VERSION 5.7 ;
  NOWIREEXTENSIONATPIN ON ;
  DIVIDERCHAR "/" ;
  BUSBITCHARS "[]" ;
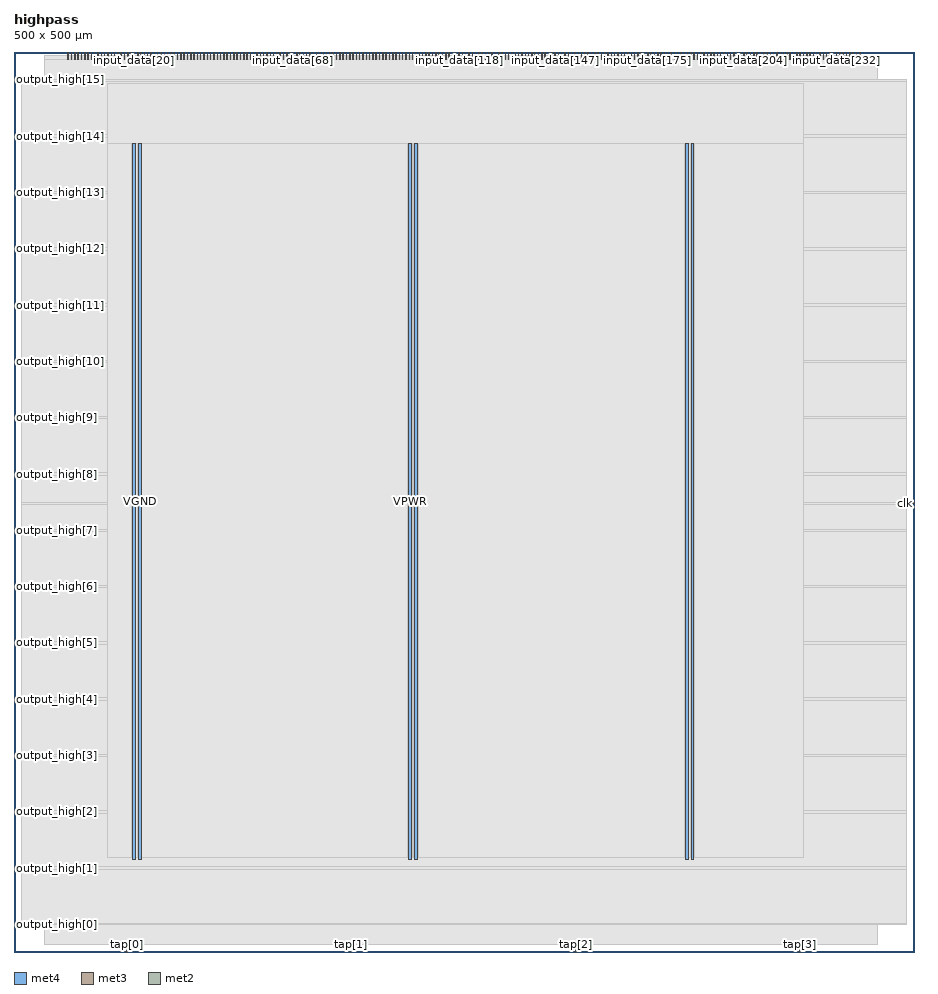
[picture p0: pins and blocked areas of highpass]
MACRO highpass
  CLASS BLOCK ;
  FOREIGN highpass ;
  ORIGIN 0.000 0.000 ;
  SIZE 500.000 BY 500.000 ;
  PIN VGND
    DIRECTION INOUT ;
    USE GROUND ;
    PORT
      LAYER met4 ;
        RECT 68.960 51.440 70.560 449.040 ;
    END
    PORT
      LAYER met4 ;
        RECT 222.560 51.440 224.160 449.040 ;
    END
    PORT
      LAYER met4 ;
        RECT 376.160 51.440 377.760 449.040 ;
    END
  END VGND
  PIN VPWR
    DIRECTION INOUT ;
    USE POWER ;
    PORT
      LAYER met4 ;
        RECT 65.660 51.440 67.260 449.040 ;
    END
    PORT
      LAYER met4 ;
        RECT 219.260 51.440 220.860 449.040 ;
    END
    PORT
      LAYER met4 ;
        RECT 372.860 51.440 374.460 449.040 ;
    END
  END VPWR
  PIN clk
    DIRECTION INPUT ;
    USE SIGNAL ;
    ANTENNAGATEAREA 0.852000 ;
    ANTENNADIFFAREA 0.434700 ;
    PORT
      LAYER met3 ;
        RECT 496.000 248.920 500.000 249.520 ;
    END
  END clk
  PIN input_data[0]
    DIRECTION INPUT ;
    USE SIGNAL ;
    ANTENNAGATEAREA 0.213000 ;
    ANTENNADIFFAREA 0.434700 ;
    PORT
      LAYER met2 ;
        RECT 29.990 496.000 30.270 500.000 ;
    END
  END input_data[0]
  PIN input_data[100]
    DIRECTION INPUT ;
    USE SIGNAL ;
    ANTENNAGATEAREA 0.213000 ;
    ANTENNADIFFAREA 0.434700 ;
    PORT
      LAYER met2 ;
        RECT 213.990 496.000 214.270 500.000 ;
    END
  END input_data[100]
  PIN input_data[101]
    DIRECTION INPUT ;
    USE SIGNAL ;
    ANTENNAGATEAREA 0.196500 ;
    ANTENNADIFFAREA 0.434700 ;
    PORT
      LAYER met2 ;
        RECT 215.830 496.000 216.110 500.000 ;
    END
  END input_data[101]
  PIN input_data[102]
    DIRECTION INPUT ;
    USE SIGNAL ;
    ANTENNAGATEAREA 0.196500 ;
    ANTENNADIFFAREA 0.434700 ;
    PORT
      LAYER met2 ;
        RECT 217.670 496.000 217.950 500.000 ;
    END
  END input_data[102]
  PIN input_data[103]
    DIRECTION INPUT ;
    USE SIGNAL ;
    ANTENNAGATEAREA 0.196500 ;
    ANTENNADIFFAREA 0.434700 ;
    PORT
      LAYER met2 ;
        RECT 219.510 496.000 219.790 500.000 ;
    END
  END input_data[103]
  PIN input_data[104]
    DIRECTION INPUT ;
    USE SIGNAL ;
    ANTENNAGATEAREA 0.196500 ;
    ANTENNADIFFAREA 0.434700 ;
    PORT
      LAYER met2 ;
        RECT 221.350 496.000 221.630 500.000 ;
    END
  END input_data[104]
  PIN input_data[105]
    DIRECTION INPUT ;
    USE SIGNAL ;
    ANTENNAGATEAREA 0.196500 ;
    ANTENNADIFFAREA 0.434700 ;
    PORT
      LAYER met2 ;
        RECT 223.190 496.000 223.470 500.000 ;
    END
  END input_data[105]
  PIN input_data[106]
    DIRECTION INPUT ;
    USE SIGNAL ;
    ANTENNAGATEAREA 0.196500 ;
    ANTENNADIFFAREA 0.434700 ;
    PORT
      LAYER met2 ;
        RECT 225.030 496.000 225.310 500.000 ;
    END
  END input_data[106]
  PIN input_data[107]
    DIRECTION INPUT ;
    USE SIGNAL ;
    ANTENNAGATEAREA 0.196500 ;
    ANTENNADIFFAREA 0.434700 ;
    PORT
      LAYER met2 ;
        RECT 226.870 496.000 227.150 500.000 ;
    END
  END input_data[107]
  PIN input_data[108]
    DIRECTION INPUT ;
    USE SIGNAL ;
    ANTENNAGATEAREA 0.159000 ;
    ANTENNADIFFAREA 0.434700 ;
    PORT
      LAYER met2 ;
        RECT 228.710 496.000 228.990 500.000 ;
    END
  END input_data[108]
  PIN input_data[109]
    DIRECTION INPUT ;
    USE SIGNAL ;
    ANTENNAGATEAREA 0.196500 ;
    ANTENNADIFFAREA 0.434700 ;
    PORT
      LAYER met2 ;
        RECT 230.550 496.000 230.830 500.000 ;
    END
  END input_data[109]
  PIN input_data[10]
    DIRECTION INPUT ;
    USE SIGNAL ;
    ANTENNAGATEAREA 0.247500 ;
    ANTENNADIFFAREA 0.434700 ;
    PORT
      LAYER met2 ;
        RECT 48.390 496.000 48.670 500.000 ;
    END
  END input_data[10]
  PIN input_data[110]
    DIRECTION INPUT ;
    USE SIGNAL ;
    ANTENNAGATEAREA 0.196500 ;
    ANTENNADIFFAREA 0.434700 ;
    PORT
      LAYER met2 ;
        RECT 232.390 496.000 232.670 500.000 ;
    END
  END input_data[110]
  PIN input_data[111]
    DIRECTION INPUT ;
    USE SIGNAL ;
    ANTENNAGATEAREA 0.196500 ;
    ANTENNADIFFAREA 0.434700 ;
    PORT
      LAYER met2 ;
        RECT 234.230 496.000 234.510 500.000 ;
    END
  END input_data[111]
  PIN input_data[112]
    DIRECTION INPUT ;
    USE SIGNAL ;
    ANTENNAGATEAREA 0.213000 ;
    ANTENNADIFFAREA 0.434700 ;
    PORT
      LAYER met2 ;
        RECT 236.070 496.000 236.350 500.000 ;
    END
  END input_data[112]
  PIN input_data[113]
    DIRECTION INPUT ;
    USE SIGNAL ;
    ANTENNAGATEAREA 0.196500 ;
    ANTENNADIFFAREA 0.434700 ;
    PORT
      LAYER met2 ;
        RECT 237.910 496.000 238.190 500.000 ;
    END
  END input_data[113]
  PIN input_data[114]
    DIRECTION INPUT ;
    USE SIGNAL ;
    ANTENNAGATEAREA 0.213000 ;
    ANTENNADIFFAREA 0.434700 ;
    PORT
      LAYER met2 ;
        RECT 239.750 496.000 240.030 500.000 ;
    END
  END input_data[114]
  PIN input_data[115]
    DIRECTION INPUT ;
    USE SIGNAL ;
    ANTENNAGATEAREA 0.213000 ;
    ANTENNADIFFAREA 0.434700 ;
    PORT
      LAYER met2 ;
        RECT 241.590 496.000 241.870 500.000 ;
    END
  END input_data[115]
  PIN input_data[116]
    DIRECTION INPUT ;
    USE SIGNAL ;
    ANTENNAGATEAREA 0.196500 ;
    ANTENNADIFFAREA 0.434700 ;
    PORT
      LAYER met2 ;
        RECT 243.430 496.000 243.710 500.000 ;
    END
  END input_data[116]
  PIN input_data[117]
    DIRECTION INPUT ;
    USE SIGNAL ;
    ANTENNAGATEAREA 0.196500 ;
    ANTENNADIFFAREA 0.434700 ;
    PORT
      LAYER met2 ;
        RECT 245.270 496.000 245.550 500.000 ;
    END
  END input_data[117]
  PIN input_data[118]
    DIRECTION INPUT ;
    USE SIGNAL ;
    ANTENNAGATEAREA 0.196500 ;
    ANTENNADIFFAREA 0.434700 ;
    PORT
      LAYER met2 ;
        RECT 247.110 496.000 247.390 500.000 ;
    END
  END input_data[118]
  PIN input_data[119]
    DIRECTION INPUT ;
    USE SIGNAL ;
    ANTENNAGATEAREA 0.196500 ;
    ANTENNADIFFAREA 0.434700 ;
    PORT
      LAYER met2 ;
        RECT 248.950 496.000 249.230 500.000 ;
    END
  END input_data[119]
  PIN input_data[11]
    DIRECTION INPUT ;
    USE SIGNAL ;
    ANTENNAGATEAREA 0.213000 ;
    ANTENNADIFFAREA 0.434700 ;
    PORT
      LAYER met2 ;
        RECT 50.230 496.000 50.510 500.000 ;
    END
  END input_data[11]
  PIN input_data[120]
    DIRECTION INPUT ;
    USE SIGNAL ;
    ANTENNAGATEAREA 0.196500 ;
    ANTENNADIFFAREA 0.434700 ;
    PORT
      LAYER met2 ;
        RECT 250.790 496.000 251.070 500.000 ;
    END
  END input_data[120]
  PIN input_data[121]
    DIRECTION INPUT ;
    USE SIGNAL ;
    ANTENNAGATEAREA 0.196500 ;
    ANTENNADIFFAREA 0.434700 ;
    PORT
      LAYER met2 ;
        RECT 252.630 496.000 252.910 500.000 ;
    END
  END input_data[121]
  PIN input_data[122]
    DIRECTION INPUT ;
    USE SIGNAL ;
    ANTENNAGATEAREA 0.159000 ;
    ANTENNADIFFAREA 0.434700 ;
    PORT
      LAYER met2 ;
        RECT 254.470 496.000 254.750 500.000 ;
    END
  END input_data[122]
  PIN input_data[123]
    DIRECTION INPUT ;
    USE SIGNAL ;
    ANTENNAGATEAREA 0.159000 ;
    ANTENNADIFFAREA 0.434700 ;
    PORT
      LAYER met2 ;
        RECT 256.310 496.000 256.590 500.000 ;
    END
  END input_data[123]
  PIN input_data[124]
    DIRECTION INPUT ;
    USE SIGNAL ;
    ANTENNAGATEAREA 0.213000 ;
    ANTENNADIFFAREA 0.434700 ;
    PORT
      LAYER met2 ;
        RECT 258.150 496.000 258.430 500.000 ;
    END
  END input_data[124]
  PIN input_data[125]
    DIRECTION INPUT ;
    USE SIGNAL ;
    ANTENNAGATEAREA 0.196500 ;
    ANTENNADIFFAREA 0.434700 ;
    PORT
      LAYER met2 ;
        RECT 259.990 496.000 260.270 500.000 ;
    END
  END input_data[125]
  PIN input_data[126]
    DIRECTION INPUT ;
    USE SIGNAL ;
    ANTENNAGATEAREA 0.196500 ;
    ANTENNADIFFAREA 0.434700 ;
    PORT
      LAYER met2 ;
        RECT 261.830 496.000 262.110 500.000 ;
    END
  END input_data[126]
  PIN input_data[127]
    DIRECTION INPUT ;
    USE SIGNAL ;
    PORT
      LAYER met2 ;
        RECT 263.670 496.000 263.950 500.000 ;
    END
  END input_data[127]
  PIN input_data[128]
    DIRECTION INPUT ;
    USE SIGNAL ;
    ANTENNAGATEAREA 0.196500 ;
    ANTENNADIFFAREA 0.434700 ;
    PORT
      LAYER met2 ;
        RECT 265.510 496.000 265.790 500.000 ;
    END
  END input_data[128]
  PIN input_data[129]
    DIRECTION INPUT ;
    USE SIGNAL ;
    ANTENNAGATEAREA 0.213000 ;
    ANTENNADIFFAREA 0.434700 ;
    PORT
      LAYER met2 ;
        RECT 267.350 496.000 267.630 500.000 ;
    END
  END input_data[129]
  PIN input_data[12]
    DIRECTION INPUT ;
    USE SIGNAL ;
    ANTENNAGATEAREA 0.495000 ;
    ANTENNADIFFAREA 0.434700 ;
    PORT
      LAYER met2 ;
        RECT 52.070 496.000 52.350 500.000 ;
    END
  END input_data[12]
  PIN input_data[130]
    DIRECTION INPUT ;
    USE SIGNAL ;
    ANTENNAGATEAREA 0.213000 ;
    ANTENNADIFFAREA 0.434700 ;
    PORT
      LAYER met2 ;
        RECT 269.190 496.000 269.470 500.000 ;
    END
  END input_data[130]
  PIN input_data[131]
    DIRECTION INPUT ;
    USE SIGNAL ;
    ANTENNAGATEAREA 0.213000 ;
    ANTENNADIFFAREA 0.434700 ;
    PORT
      LAYER met2 ;
        RECT 271.030 496.000 271.310 500.000 ;
    END
  END input_data[131]
  PIN input_data[132]
    DIRECTION INPUT ;
    USE SIGNAL ;
    ANTENNAGATEAREA 0.213000 ;
    ANTENNADIFFAREA 0.434700 ;
    PORT
      LAYER met2 ;
        RECT 272.870 496.000 273.150 500.000 ;
    END
  END input_data[132]
  PIN input_data[133]
    DIRECTION INPUT ;
    USE SIGNAL ;
    ANTENNAGATEAREA 0.247500 ;
    ANTENNADIFFAREA 0.434700 ;
    PORT
      LAYER met2 ;
        RECT 274.710 496.000 274.990 500.000 ;
    END
  END input_data[133]
  PIN input_data[134]
    DIRECTION INPUT ;
    USE SIGNAL ;
    ANTENNAGATEAREA 0.213000 ;
    ANTENNADIFFAREA 0.434700 ;
    PORT
      LAYER met2 ;
        RECT 276.550 496.000 276.830 500.000 ;
    END
  END input_data[134]
  PIN input_data[135]
    DIRECTION INPUT ;
    USE SIGNAL ;
    ANTENNAGATEAREA 0.213000 ;
    ANTENNADIFFAREA 0.434700 ;
    PORT
      LAYER met2 ;
        RECT 278.390 496.000 278.670 500.000 ;
    END
  END input_data[135]
  PIN input_data[136]
    DIRECTION INPUT ;
    USE SIGNAL ;
    ANTENNAGATEAREA 0.495000 ;
    ANTENNADIFFAREA 0.434700 ;
    PORT
      LAYER met2 ;
        RECT 280.230 496.000 280.510 500.000 ;
    END
  END input_data[136]
  PIN input_data[137]
    DIRECTION INPUT ;
    USE SIGNAL ;
    ANTENNAGATEAREA 0.247500 ;
    ANTENNADIFFAREA 0.434700 ;
    PORT
      LAYER met2 ;
        RECT 282.070 496.000 282.350 500.000 ;
    END
  END input_data[137]
  PIN input_data[138]
    DIRECTION INPUT ;
    USE SIGNAL ;
    ANTENNAGATEAREA 0.159000 ;
    ANTENNADIFFAREA 0.434700 ;
    PORT
      LAYER met2 ;
        RECT 283.910 496.000 284.190 500.000 ;
    END
  END input_data[138]
  PIN input_data[139]
    DIRECTION INPUT ;
    USE SIGNAL ;
    ANTENNAGATEAREA 0.247500 ;
    ANTENNADIFFAREA 0.434700 ;
    PORT
      LAYER met2 ;
        RECT 285.750 496.000 286.030 500.000 ;
    END
  END input_data[139]
  PIN input_data[13]
    DIRECTION INPUT ;
    USE SIGNAL ;
    ANTENNAGATEAREA 0.426000 ;
    ANTENNADIFFAREA 0.434700 ;
    PORT
      LAYER met2 ;
        RECT 53.910 496.000 54.190 500.000 ;
    END
  END input_data[13]
  PIN input_data[140]
    DIRECTION INPUT ;
    USE SIGNAL ;
    ANTENNAGATEAREA 0.247500 ;
    ANTENNADIFFAREA 0.434700 ;
    PORT
      LAYER met2 ;
        RECT 287.590 496.000 287.870 500.000 ;
    END
  END input_data[140]
  PIN input_data[141]
    DIRECTION INPUT ;
    USE SIGNAL ;
    ANTENNAGATEAREA 0.213000 ;
    ANTENNADIFFAREA 0.434700 ;
    PORT
      LAYER met2 ;
        RECT 289.430 496.000 289.710 500.000 ;
    END
  END input_data[141]
  PIN input_data[142]
    DIRECTION INPUT ;
    USE SIGNAL ;
    ANTENNAGATEAREA 0.196500 ;
    ANTENNADIFFAREA 0.434700 ;
    PORT
      LAYER met2 ;
        RECT 291.270 496.000 291.550 500.000 ;
    END
  END input_data[142]
  PIN input_data[143]
    DIRECTION INPUT ;
    USE SIGNAL ;
    ANTENNAGATEAREA 0.196500 ;
    ANTENNADIFFAREA 0.434700 ;
    PORT
      LAYER met2 ;
        RECT 293.110 496.000 293.390 500.000 ;
    END
  END input_data[143]
  PIN input_data[144]
    DIRECTION INPUT ;
    USE SIGNAL ;
    ANTENNAGATEAREA 0.196500 ;
    ANTENNADIFFAREA 0.434700 ;
    PORT
      LAYER met2 ;
        RECT 294.950 496.000 295.230 500.000 ;
    END
  END input_data[144]
  PIN input_data[145]
    DIRECTION INPUT ;
    USE SIGNAL ;
    ANTENNAGATEAREA 0.126000 ;
    ANTENNADIFFAREA 0.434700 ;
    PORT
      LAYER met2 ;
        RECT 296.790 496.000 297.070 500.000 ;
    END
  END input_data[145]
  PIN input_data[146]
    DIRECTION INPUT ;
    USE SIGNAL ;
    ANTENNAGATEAREA 0.126000 ;
    ANTENNADIFFAREA 0.434700 ;
    PORT
      LAYER met2 ;
        RECT 298.630 496.000 298.910 500.000 ;
    END
  END input_data[146]
  PIN input_data[147]
    DIRECTION INPUT ;
    USE SIGNAL ;
    ANTENNAGATEAREA 0.159000 ;
    ANTENNADIFFAREA 0.434700 ;
    PORT
      LAYER met2 ;
        RECT 300.470 496.000 300.750 500.000 ;
    END
  END input_data[147]
  PIN input_data[148]
    DIRECTION INPUT ;
    USE SIGNAL ;
    ANTENNAGATEAREA 0.213000 ;
    ANTENNADIFFAREA 0.434700 ;
    PORT
      LAYER met2 ;
        RECT 302.310 496.000 302.590 500.000 ;
    END
  END input_data[148]
  PIN input_data[149]
    DIRECTION INPUT ;
    USE SIGNAL ;
    ANTENNAGATEAREA 0.213000 ;
    ANTENNADIFFAREA 0.434700 ;
    PORT
      LAYER met2 ;
        RECT 304.150 496.000 304.430 500.000 ;
    END
  END input_data[149]
  PIN input_data[14]
    DIRECTION INPUT ;
    USE SIGNAL ;
    ANTENNAGATEAREA 0.159000 ;
    ANTENNADIFFAREA 0.434700 ;
    PORT
      LAYER met2 ;
        RECT 55.750 496.000 56.030 500.000 ;
    END
  END input_data[14]
  PIN input_data[150]
    DIRECTION INPUT ;
    USE SIGNAL ;
    ANTENNAGATEAREA 0.213000 ;
    ANTENNADIFFAREA 0.434700 ;
    PORT
      LAYER met2 ;
        RECT 305.990 496.000 306.270 500.000 ;
    END
  END input_data[150]
  PIN input_data[151]
    DIRECTION INPUT ;
    USE SIGNAL ;
    ANTENNAGATEAREA 0.159000 ;
    ANTENNADIFFAREA 0.434700 ;
    PORT
      LAYER met2 ;
        RECT 307.830 496.000 308.110 500.000 ;
    END
  END input_data[151]
  PIN input_data[152]
    DIRECTION INPUT ;
    USE SIGNAL ;
    ANTENNAGATEAREA 0.213000 ;
    ANTENNADIFFAREA 0.434700 ;
    PORT
      LAYER met2 ;
        RECT 309.670 496.000 309.950 500.000 ;
    END
  END input_data[152]
  PIN input_data[153]
    DIRECTION INPUT ;
    USE SIGNAL ;
    ANTENNAGATEAREA 0.213000 ;
    ANTENNADIFFAREA 0.434700 ;
    PORT
      LAYER met2 ;
        RECT 311.510 496.000 311.790 500.000 ;
    END
  END input_data[153]
  PIN input_data[154]
    DIRECTION INPUT ;
    USE SIGNAL ;
    ANTENNAGATEAREA 0.213000 ;
    ANTENNADIFFAREA 0.434700 ;
    PORT
      LAYER met2 ;
        RECT 313.350 496.000 313.630 500.000 ;
    END
  END input_data[154]
  PIN input_data[155]
    DIRECTION INPUT ;
    USE SIGNAL ;
    ANTENNAGATEAREA 0.196500 ;
    ANTENNADIFFAREA 0.434700 ;
    PORT
      LAYER met2 ;
        RECT 315.190 496.000 315.470 500.000 ;
    END
  END input_data[155]
  PIN input_data[156]
    DIRECTION INPUT ;
    USE SIGNAL ;
    ANTENNAGATEAREA 0.159000 ;
    ANTENNADIFFAREA 0.434700 ;
    PORT
      LAYER met2 ;
        RECT 317.030 496.000 317.310 500.000 ;
    END
  END input_data[156]
  PIN input_data[157]
    DIRECTION INPUT ;
    USE SIGNAL ;
    ANTENNAGATEAREA 0.213000 ;
    ANTENNADIFFAREA 0.434700 ;
    PORT
      LAYER met2 ;
        RECT 318.870 496.000 319.150 500.000 ;
    END
  END input_data[157]
  PIN input_data[158]
    DIRECTION INPUT ;
    USE SIGNAL ;
    ANTENNAGATEAREA 0.196500 ;
    ANTENNADIFFAREA 0.434700 ;
    PORT
      LAYER met2 ;
        RECT 320.710 496.000 320.990 500.000 ;
    END
  END input_data[158]
  PIN input_data[159]
    DIRECTION INPUT ;
    USE SIGNAL ;
    ANTENNAGATEAREA 0.196500 ;
    ANTENNADIFFAREA 0.434700 ;
    PORT
      LAYER met2 ;
        RECT 322.550 496.000 322.830 500.000 ;
    END
  END input_data[159]
  PIN input_data[15]
    DIRECTION INPUT ;
    USE SIGNAL ;
    ANTENNAGATEAREA 0.213000 ;
    ANTENNADIFFAREA 0.434700 ;
    PORT
      LAYER met2 ;
        RECT 57.590 496.000 57.870 500.000 ;
    END
  END input_data[15]
  PIN input_data[160]
    DIRECTION INPUT ;
    USE SIGNAL ;
    ANTENNAGATEAREA 0.247500 ;
    ANTENNADIFFAREA 0.434700 ;
    PORT
      LAYER met2 ;
        RECT 324.390 496.000 324.670 500.000 ;
    END
  END input_data[160]
  PIN input_data[161]
    DIRECTION INPUT ;
    USE SIGNAL ;
    ANTENNAGATEAREA 0.247500 ;
    ANTENNADIFFAREA 0.434700 ;
    PORT
      LAYER met2 ;
        RECT 326.230 496.000 326.510 500.000 ;
    END
  END input_data[161]
  PIN input_data[162]
    DIRECTION INPUT ;
    USE SIGNAL ;
    ANTENNAGATEAREA 0.247500 ;
    ANTENNADIFFAREA 0.434700 ;
    PORT
      LAYER met2 ;
        RECT 328.070 496.000 328.350 500.000 ;
    END
  END input_data[162]
  PIN input_data[163]
    DIRECTION INPUT ;
    USE SIGNAL ;
    ANTENNAGATEAREA 0.213000 ;
    ANTENNADIFFAREA 0.434700 ;
    PORT
      LAYER met2 ;
        RECT 329.910 496.000 330.190 500.000 ;
    END
  END input_data[163]
  PIN input_data[164]
    DIRECTION INPUT ;
    USE SIGNAL ;
    ANTENNAGATEAREA 0.126000 ;
    ANTENNADIFFAREA 0.434700 ;
    PORT
      LAYER met2 ;
        RECT 331.750 496.000 332.030 500.000 ;
    END
  END input_data[164]
  PIN input_data[165]
    DIRECTION INPUT ;
    USE SIGNAL ;
    ANTENNAGATEAREA 0.196500 ;
    ANTENNADIFFAREA 0.434700 ;
    PORT
      LAYER met2 ;
        RECT 333.590 496.000 333.870 500.000 ;
    END
  END input_data[165]
  PIN input_data[166]
    DIRECTION INPUT ;
    USE SIGNAL ;
    ANTENNAGATEAREA 0.126000 ;
    ANTENNADIFFAREA 0.434700 ;
    PORT
      LAYER met2 ;
        RECT 335.430 496.000 335.710 500.000 ;
    END
  END input_data[166]
  PIN input_data[167]
    DIRECTION INPUT ;
    USE SIGNAL ;
    ANTENNAGATEAREA 0.213000 ;
    ANTENNADIFFAREA 0.434700 ;
    PORT
      LAYER met2 ;
        RECT 337.270 496.000 337.550 500.000 ;
    END
  END input_data[167]
  PIN input_data[168]
    DIRECTION INPUT ;
    USE SIGNAL ;
    ANTENNAGATEAREA 0.196500 ;
    ANTENNADIFFAREA 0.434700 ;
    PORT
      LAYER met2 ;
        RECT 339.110 496.000 339.390 500.000 ;
    END
  END input_data[168]
  PIN input_data[169]
    DIRECTION INPUT ;
    USE SIGNAL ;
    ANTENNAGATEAREA 0.196500 ;
    ANTENNADIFFAREA 0.434700 ;
    PORT
      LAYER met2 ;
        RECT 340.950 496.000 341.230 500.000 ;
    END
  END input_data[169]
  PIN input_data[16]
    DIRECTION INPUT ;
    USE SIGNAL ;
    ANTENNAGATEAREA 0.247500 ;
    ANTENNADIFFAREA 0.434700 ;
    PORT
      LAYER met2 ;
        RECT 59.430 496.000 59.710 500.000 ;
    END
  END input_data[16]
  PIN input_data[170]
    DIRECTION INPUT ;
    USE SIGNAL ;
    ANTENNAGATEAREA 0.196500 ;
    ANTENNADIFFAREA 0.434700 ;
    PORT
      LAYER met2 ;
        RECT 342.790 496.000 343.070 500.000 ;
    END
  END input_data[170]
  PIN input_data[171]
    DIRECTION INPUT ;
    USE SIGNAL ;
    ANTENNAGATEAREA 0.213000 ;
    ANTENNADIFFAREA 0.434700 ;
    PORT
      LAYER met2 ;
        RECT 344.630 496.000 344.910 500.000 ;
    END
  END input_data[171]
  PIN input_data[172]
    DIRECTION INPUT ;
    USE SIGNAL ;
    ANTENNAGATEAREA 0.213000 ;
    ANTENNADIFFAREA 0.434700 ;
    PORT
      LAYER met2 ;
        RECT 346.470 496.000 346.750 500.000 ;
    END
  END input_data[172]
  PIN input_data[173]
    DIRECTION INPUT ;
    USE SIGNAL ;
    ANTENNAGATEAREA 0.213000 ;
    ANTENNADIFFAREA 0.434700 ;
    PORT
      LAYER met2 ;
        RECT 348.310 496.000 348.590 500.000 ;
    END
  END input_data[173]
  PIN input_data[174]
    DIRECTION INPUT ;
    USE SIGNAL ;
    ANTENNAGATEAREA 0.196500 ;
    ANTENNADIFFAREA 0.434700 ;
    PORT
      LAYER met2 ;
        RECT 350.150 496.000 350.430 500.000 ;
    END
  END input_data[174]
  PIN input_data[175]
    DIRECTION INPUT ;
    USE SIGNAL ;
    ANTENNAGATEAREA 0.196500 ;
    ANTENNADIFFAREA 0.434700 ;
    PORT
      LAYER met2 ;
        RECT 351.990 496.000 352.270 500.000 ;
    END
  END input_data[175]
  PIN input_data[176]
    DIRECTION INPUT ;
    USE SIGNAL ;
    ANTENNAGATEAREA 0.126000 ;
    ANTENNADIFFAREA 0.434700 ;
    PORT
      LAYER met2 ;
        RECT 353.830 496.000 354.110 500.000 ;
    END
  END input_data[176]
  PIN input_data[177]
    DIRECTION INPUT ;
    USE SIGNAL ;
    ANTENNAGATEAREA 0.213000 ;
    ANTENNADIFFAREA 0.434700 ;
    PORT
      LAYER met2 ;
        RECT 355.670 496.000 355.950 500.000 ;
    END
  END input_data[177]
  PIN input_data[178]
    DIRECTION INPUT ;
    USE SIGNAL ;
    ANTENNAGATEAREA 0.213000 ;
    ANTENNADIFFAREA 0.434700 ;
    PORT
      LAYER met2 ;
        RECT 357.510 496.000 357.790 500.000 ;
    END
  END input_data[178]
  PIN input_data[179]
    DIRECTION INPUT ;
    USE SIGNAL ;
    ANTENNAGATEAREA 0.213000 ;
    ANTENNADIFFAREA 0.434700 ;
    PORT
      LAYER met2 ;
        RECT 359.350 496.000 359.630 500.000 ;
    END
  END input_data[179]
  PIN input_data[17]
    DIRECTION INPUT ;
    USE SIGNAL ;
    ANTENNAGATEAREA 0.247500 ;
    ANTENNADIFFAREA 0.434700 ;
    PORT
      LAYER met2 ;
        RECT 61.270 496.000 61.550 500.000 ;
    END
  END input_data[17]
  PIN input_data[180]
    DIRECTION INPUT ;
    USE SIGNAL ;
    ANTENNAGATEAREA 0.213000 ;
    ANTENNADIFFAREA 0.434700 ;
    PORT
      LAYER met2 ;
        RECT 361.190 496.000 361.470 500.000 ;
    END
  END input_data[180]
  PIN input_data[181]
    DIRECTION INPUT ;
    USE SIGNAL ;
    ANTENNAGATEAREA 0.159000 ;
    ANTENNADIFFAREA 0.434700 ;
    PORT
      LAYER met2 ;
        RECT 363.030 496.000 363.310 500.000 ;
    END
  END input_data[181]
  PIN input_data[182]
    DIRECTION INPUT ;
    USE SIGNAL ;
    ANTENNAGATEAREA 0.159000 ;
    ANTENNADIFFAREA 0.434700 ;
    PORT
      LAYER met2 ;
        RECT 364.870 496.000 365.150 500.000 ;
    END
  END input_data[182]
  PIN input_data[183]
    DIRECTION INPUT ;
    USE SIGNAL ;
    ANTENNAGATEAREA 0.159000 ;
    ANTENNADIFFAREA 0.434700 ;
    PORT
      LAYER met2 ;
        RECT 366.710 496.000 366.990 500.000 ;
    END
  END input_data[183]
  PIN input_data[184]
    DIRECTION INPUT ;
    USE SIGNAL ;
    ANTENNAGATEAREA 0.159000 ;
    ANTENNADIFFAREA 0.434700 ;
    PORT
      LAYER met2 ;
        RECT 368.550 496.000 368.830 500.000 ;
    END
  END input_data[184]
  PIN input_data[185]
    DIRECTION INPUT ;
    USE SIGNAL ;
    ANTENNAGATEAREA 0.213000 ;
    ANTENNADIFFAREA 0.434700 ;
    PORT
      LAYER met2 ;
        RECT 370.390 496.000 370.670 500.000 ;
    END
  END input_data[185]
  PIN input_data[186]
    DIRECTION INPUT ;
    USE SIGNAL ;
    ANTENNAGATEAREA 0.213000 ;
    ANTENNADIFFAREA 0.434700 ;
    PORT
      LAYER met2 ;
        RECT 372.230 496.000 372.510 500.000 ;
    END
  END input_data[186]
  PIN input_data[187]
    DIRECTION INPUT ;
    USE SIGNAL ;
    ANTENNAGATEAREA 0.213000 ;
    ANTENNADIFFAREA 0.434700 ;
    PORT
      LAYER met2 ;
        RECT 374.070 496.000 374.350 500.000 ;
    END
  END input_data[187]
  PIN input_data[188]
    DIRECTION INPUT ;
    USE SIGNAL ;
    ANTENNAGATEAREA 0.159000 ;
    ANTENNADIFFAREA 0.434700 ;
    PORT
      LAYER met2 ;
        RECT 375.910 496.000 376.190 500.000 ;
    END
  END input_data[188]
  PIN input_data[189]
    DIRECTION INPUT ;
    USE SIGNAL ;
    ANTENNAGATEAREA 0.196500 ;
    ANTENNADIFFAREA 0.434700 ;
    PORT
      LAYER met2 ;
        RECT 377.750 496.000 378.030 500.000 ;
    END
  END input_data[189]
  PIN input_data[18]
    DIRECTION INPUT ;
    USE SIGNAL ;
    ANTENNAGATEAREA 0.213000 ;
    ANTENNADIFFAREA 0.434700 ;
    PORT
      LAYER met2 ;
        RECT 63.110 496.000 63.390 500.000 ;
    END
  END input_data[18]
  PIN input_data[190]
    DIRECTION INPUT ;
    USE SIGNAL ;
    ANTENNAGATEAREA 0.196500 ;
    ANTENNADIFFAREA 0.434700 ;
    PORT
      LAYER met2 ;
        RECT 379.590 496.000 379.870 500.000 ;
    END
  END input_data[190]
  PIN input_data[191]
    DIRECTION INPUT ;
    USE SIGNAL ;
    PORT
      LAYER met2 ;
        RECT 381.430 496.000 381.710 500.000 ;
    END
  END input_data[191]
  PIN input_data[192]
    DIRECTION INPUT ;
    USE SIGNAL ;
    ANTENNAGATEAREA 0.213000 ;
    ANTENNADIFFAREA 0.434700 ;
    PORT
      LAYER met2 ;
        RECT 383.270 496.000 383.550 500.000 ;
    END
  END input_data[192]
  PIN input_data[193]
    DIRECTION INPUT ;
    USE SIGNAL ;
    ANTENNAGATEAREA 0.126000 ;
    ANTENNADIFFAREA 0.434700 ;
    PORT
      LAYER met2 ;
        RECT 385.110 496.000 385.390 500.000 ;
    END
  END input_data[193]
  PIN input_data[194]
    DIRECTION INPUT ;
    USE SIGNAL ;
    ANTENNAGATEAREA 0.213000 ;
    ANTENNADIFFAREA 0.434700 ;
    PORT
      LAYER met2 ;
        RECT 386.950 496.000 387.230 500.000 ;
    END
  END input_data[194]
  PIN input_data[195]
    DIRECTION INPUT ;
    USE SIGNAL ;
    ANTENNAGATEAREA 0.213000 ;
    ANTENNADIFFAREA 0.434700 ;
    PORT
      LAYER met2 ;
        RECT 388.790 496.000 389.070 500.000 ;
    END
  END input_data[195]
  PIN input_data[196]
    DIRECTION INPUT ;
    USE SIGNAL ;
    ANTENNAGATEAREA 0.213000 ;
    ANTENNADIFFAREA 0.434700 ;
    PORT
      LAYER met2 ;
        RECT 390.630 496.000 390.910 500.000 ;
    END
  END input_data[196]
  PIN input_data[197]
    DIRECTION INPUT ;
    USE SIGNAL ;
    ANTENNAGATEAREA 0.126000 ;
    ANTENNADIFFAREA 0.434700 ;
    PORT
      LAYER met2 ;
        RECT 392.470 496.000 392.750 500.000 ;
    END
  END input_data[197]
  PIN input_data[198]
    DIRECTION INPUT ;
    USE SIGNAL ;
    ANTENNAGATEAREA 0.126000 ;
    ANTENNADIFFAREA 0.434700 ;
    PORT
      LAYER met2 ;
        RECT 394.310 496.000 394.590 500.000 ;
    END
  END input_data[198]
  PIN input_data[199]
    DIRECTION INPUT ;
    USE SIGNAL ;
    ANTENNAGATEAREA 0.126000 ;
    ANTENNADIFFAREA 0.434700 ;
    PORT
      LAYER met2 ;
        RECT 396.150 496.000 396.430 500.000 ;
    END
  END input_data[199]
  PIN input_data[19]
    DIRECTION INPUT ;
    USE SIGNAL ;
    ANTENNAGATEAREA 0.247500 ;
    ANTENNADIFFAREA 0.434700 ;
    PORT
      LAYER met2 ;
        RECT 64.950 496.000 65.230 500.000 ;
    END
  END input_data[19]
  PIN input_data[1]
    DIRECTION INPUT ;
    USE SIGNAL ;
    ANTENNAGATEAREA 0.159000 ;
    ANTENNADIFFAREA 0.434700 ;
    PORT
      LAYER met2 ;
        RECT 31.830 496.000 32.110 500.000 ;
    END
  END input_data[1]
  PIN input_data[200]
    DIRECTION INPUT ;
    USE SIGNAL ;
    ANTENNAGATEAREA 0.126000 ;
    ANTENNADIFFAREA 0.434700 ;
    PORT
      LAYER met2 ;
        RECT 397.990 496.000 398.270 500.000 ;
    END
  END input_data[200]
  PIN input_data[201]
    DIRECTION INPUT ;
    USE SIGNAL ;
    ANTENNAGATEAREA 0.126000 ;
    ANTENNADIFFAREA 0.434700 ;
    PORT
      LAYER met2 ;
        RECT 399.830 496.000 400.110 500.000 ;
    END
  END input_data[201]
  PIN input_data[202]
    DIRECTION INPUT ;
    USE SIGNAL ;
    ANTENNAGATEAREA 0.126000 ;
    ANTENNADIFFAREA 0.434700 ;
    PORT
      LAYER met2 ;
        RECT 401.670 496.000 401.950 500.000 ;
    END
  END input_data[202]
  PIN input_data[203]
    DIRECTION INPUT ;
    USE SIGNAL ;
    ANTENNAGATEAREA 0.126000 ;
    ANTENNADIFFAREA 0.434700 ;
    PORT
      LAYER met2 ;
        RECT 403.510 496.000 403.790 500.000 ;
    END
  END input_data[203]
  PIN input_data[204]
    DIRECTION INPUT ;
    USE SIGNAL ;
    ANTENNAGATEAREA 0.196500 ;
    ANTENNADIFFAREA 0.434700 ;
    PORT
      LAYER met2 ;
        RECT 405.350 496.000 405.630 500.000 ;
    END
  END input_data[204]
  PIN input_data[205]
    DIRECTION INPUT ;
    USE SIGNAL ;
    ANTENNAGATEAREA 0.196500 ;
    ANTENNADIFFAREA 0.434700 ;
    PORT
      LAYER met2 ;
        RECT 407.190 496.000 407.470 500.000 ;
    END
  END input_data[205]
  PIN input_data[206]
    DIRECTION INPUT ;
    USE SIGNAL ;
    ANTENNAGATEAREA 0.196500 ;
    ANTENNADIFFAREA 0.434700 ;
    PORT
      LAYER met2 ;
        RECT 409.030 496.000 409.310 500.000 ;
    END
  END input_data[206]
  PIN input_data[207]
    DIRECTION INPUT ;
    USE SIGNAL ;
    PORT
      LAYER met2 ;
        RECT 410.870 496.000 411.150 500.000 ;
    END
  END input_data[207]
  PIN input_data[208]
    DIRECTION INPUT ;
    USE SIGNAL ;
    PORT
      LAYER met2 ;
        RECT 412.710 496.000 412.990 500.000 ;
    END
  END input_data[208]
  PIN input_data[209]
    DIRECTION INPUT ;
    USE SIGNAL ;
    PORT
      LAYER met2 ;
        RECT 414.550 496.000 414.830 500.000 ;
    END
  END input_data[209]
  PIN input_data[20]
    DIRECTION INPUT ;
    USE SIGNAL ;
    ANTENNAGATEAREA 0.247500 ;
    ANTENNADIFFAREA 0.434700 ;
    PORT
      LAYER met2 ;
        RECT 66.790 496.000 67.070 500.000 ;
    END
  END input_data[20]
  PIN input_data[210]
    DIRECTION INPUT ;
    USE SIGNAL ;
    PORT
      LAYER met2 ;
        RECT 416.390 496.000 416.670 500.000 ;
    END
  END input_data[210]
  PIN input_data[211]
    DIRECTION INPUT ;
    USE SIGNAL ;
    PORT
      LAYER met2 ;
        RECT 418.230 496.000 418.510 500.000 ;
    END
  END input_data[211]
  PIN input_data[212]
    DIRECTION INPUT ;
    USE SIGNAL ;
    PORT
      LAYER met2 ;
        RECT 420.070 496.000 420.350 500.000 ;
    END
  END input_data[212]
  PIN input_data[213]
    DIRECTION INPUT ;
    USE SIGNAL ;
    PORT
      LAYER met2 ;
        RECT 421.910 496.000 422.190 500.000 ;
    END
  END input_data[213]
  PIN input_data[214]
    DIRECTION INPUT ;
    USE SIGNAL ;
    PORT
      LAYER met2 ;
        RECT 423.750 496.000 424.030 500.000 ;
    END
  END input_data[214]
  PIN input_data[215]
    DIRECTION INPUT ;
    USE SIGNAL ;
    PORT
      LAYER met2 ;
        RECT 425.590 496.000 425.870 500.000 ;
    END
  END input_data[215]
  PIN input_data[216]
    DIRECTION INPUT ;
    USE SIGNAL ;
    PORT
      LAYER met2 ;
        RECT 427.430 496.000 427.710 500.000 ;
    END
  END input_data[216]
  PIN input_data[217]
    DIRECTION INPUT ;
    USE SIGNAL ;
    PORT
      LAYER met2 ;
        RECT 429.270 496.000 429.550 500.000 ;
    END
  END input_data[217]
  PIN input_data[218]
    DIRECTION INPUT ;
    USE SIGNAL ;
    PORT
      LAYER met2 ;
        RECT 431.110 496.000 431.390 500.000 ;
    END
  END input_data[218]
  PIN input_data[219]
    DIRECTION INPUT ;
    USE SIGNAL ;
    PORT
      LAYER met2 ;
        RECT 432.950 496.000 433.230 500.000 ;
    END
  END input_data[219]
  PIN input_data[21]
    DIRECTION INPUT ;
    USE SIGNAL ;
    ANTENNAGATEAREA 0.247500 ;
    ANTENNADIFFAREA 0.434700 ;
    PORT
      LAYER met2 ;
        RECT 68.630 496.000 68.910 500.000 ;
    END
  END input_data[21]
  PIN input_data[220]
    DIRECTION INPUT ;
    USE SIGNAL ;
    PORT
      LAYER met2 ;
        RECT 434.790 496.000 435.070 500.000 ;
    END
  END input_data[220]
  PIN input_data[221]
    DIRECTION INPUT ;
    USE SIGNAL ;
    PORT
      LAYER met2 ;
        RECT 436.630 496.000 436.910 500.000 ;
    END
  END input_data[221]
  PIN input_data[222]
    DIRECTION INPUT ;
    USE SIGNAL ;
    PORT
      LAYER met2 ;
        RECT 438.470 496.000 438.750 500.000 ;
    END
  END input_data[222]
  PIN input_data[223]
    DIRECTION INPUT ;
    USE SIGNAL ;
    PORT
      LAYER met2 ;
        RECT 440.310 496.000 440.590 500.000 ;
    END
  END input_data[223]
  PIN input_data[224]
    DIRECTION INPUT ;
    USE SIGNAL ;
    ANTENNAGATEAREA 0.213000 ;
    ANTENNADIFFAREA 0.434700 ;
    PORT
      LAYER met2 ;
        RECT 442.150 496.000 442.430 500.000 ;
    END
  END input_data[224]
  PIN input_data[225]
    DIRECTION INPUT ;
    USE SIGNAL ;
    ANTENNAGATEAREA 0.247500 ;
    ANTENNADIFFAREA 0.434700 ;
    PORT
      LAYER met2 ;
        RECT 443.990 496.000 444.270 500.000 ;
    END
  END input_data[225]
  PIN input_data[226]
    DIRECTION INPUT ;
    USE SIGNAL ;
    ANTENNAGATEAREA 0.213000 ;
    ANTENNADIFFAREA 0.434700 ;
    PORT
      LAYER met2 ;
        RECT 445.830 496.000 446.110 500.000 ;
    END
  END input_data[226]
  PIN input_data[227]
    DIRECTION INPUT ;
    USE SIGNAL ;
    ANTENNAGATEAREA 0.213000 ;
    ANTENNADIFFAREA 0.434700 ;
    PORT
      LAYER met2 ;
        RECT 447.670 496.000 447.950 500.000 ;
    END
  END input_data[227]
  PIN input_data[228]
    DIRECTION INPUT ;
    USE SIGNAL ;
    ANTENNAGATEAREA 0.213000 ;
    ANTENNADIFFAREA 0.434700 ;
    PORT
      LAYER met2 ;
        RECT 449.510 496.000 449.790 500.000 ;
    END
  END input_data[228]
  PIN input_data[229]
    DIRECTION INPUT ;
    USE SIGNAL ;
    ANTENNAGATEAREA 0.213000 ;
    ANTENNADIFFAREA 0.434700 ;
    PORT
      LAYER met2 ;
        RECT 451.350 496.000 451.630 500.000 ;
    END
  END input_data[229]
  PIN input_data[22]
    DIRECTION INPUT ;
    USE SIGNAL ;
    ANTENNAGATEAREA 0.247500 ;
    ANTENNADIFFAREA 0.434700 ;
    PORT
      LAYER met2 ;
        RECT 70.470 496.000 70.750 500.000 ;
    END
  END input_data[22]
  PIN input_data[230]
    DIRECTION INPUT ;
    USE SIGNAL ;
    ANTENNAGATEAREA 0.213000 ;
    ANTENNADIFFAREA 0.434700 ;
    PORT
      LAYER met2 ;
        RECT 453.190 496.000 453.470 500.000 ;
    END
  END input_data[230]
  PIN input_data[231]
    DIRECTION INPUT ;
    USE SIGNAL ;
    ANTENNAGATEAREA 0.213000 ;
    ANTENNADIFFAREA 0.434700 ;
    PORT
      LAYER met2 ;
        RECT 455.030 496.000 455.310 500.000 ;
    END
  END input_data[231]
  PIN input_data[232]
    DIRECTION INPUT ;
    USE SIGNAL ;
    ANTENNAGATEAREA 0.126000 ;
    ANTENNADIFFAREA 0.434700 ;
    PORT
      LAYER met2 ;
        RECT 456.870 496.000 457.150 500.000 ;
    END
  END input_data[232]
  PIN input_data[233]
    DIRECTION INPUT ;
    USE SIGNAL ;
    ANTENNAGATEAREA 0.126000 ;
    ANTENNADIFFAREA 0.434700 ;
    PORT
      LAYER met2 ;
        RECT 458.710 496.000 458.990 500.000 ;
    END
  END input_data[233]
  PIN input_data[234]
    DIRECTION INPUT ;
    USE SIGNAL ;
    ANTENNAGATEAREA 0.126000 ;
    ANTENNADIFFAREA 0.434700 ;
    PORT
      LAYER met2 ;
        RECT 460.550 496.000 460.830 500.000 ;
    END
  END input_data[234]
  PIN input_data[235]
    DIRECTION INPUT ;
    USE SIGNAL ;
    ANTENNAGATEAREA 0.196500 ;
    ANTENNADIFFAREA 0.434700 ;
    PORT
      LAYER met2 ;
        RECT 462.390 496.000 462.670 500.000 ;
    END
  END input_data[235]
  PIN input_data[236]
    DIRECTION INPUT ;
    USE SIGNAL ;
    ANTENNAGATEAREA 0.196500 ;
    ANTENNADIFFAREA 0.434700 ;
    PORT
      LAYER met2 ;
        RECT 464.230 496.000 464.510 500.000 ;
    END
  END input_data[236]
  PIN input_data[237]
    DIRECTION INPUT ;
    USE SIGNAL ;
    ANTENNAGATEAREA 0.196500 ;
    ANTENNADIFFAREA 0.434700 ;
    PORT
      LAYER met2 ;
        RECT 466.070 496.000 466.350 500.000 ;
    END
  END input_data[237]
  PIN input_data[238]
    DIRECTION INPUT ;
    USE SIGNAL ;
    PORT
      LAYER met2 ;
        RECT 467.910 496.000 468.190 500.000 ;
    END
  END input_data[238]
  PIN input_data[239]
    DIRECTION INPUT ;
    USE SIGNAL ;
    PORT
      LAYER met2 ;
        RECT 469.750 496.000 470.030 500.000 ;
    END
  END input_data[239]
  PIN input_data[23]
    DIRECTION INPUT ;
    USE SIGNAL ;
    ANTENNAGATEAREA 0.247500 ;
    ANTENNADIFFAREA 0.434700 ;
    PORT
      LAYER met2 ;
        RECT 72.310 496.000 72.590 500.000 ;
    END
  END input_data[23]
  PIN input_data[24]
    DIRECTION INPUT ;
    USE SIGNAL ;
    ANTENNAGATEAREA 0.247500 ;
    ANTENNADIFFAREA 0.434700 ;
    PORT
      LAYER met2 ;
        RECT 74.150 496.000 74.430 500.000 ;
    END
  END input_data[24]
  PIN input_data[25]
    DIRECTION INPUT ;
    USE SIGNAL ;
    ANTENNAGATEAREA 0.213000 ;
    ANTENNADIFFAREA 0.434700 ;
    PORT
      LAYER met2 ;
        RECT 75.990 496.000 76.270 500.000 ;
    END
  END input_data[25]
  PIN input_data[26]
    DIRECTION INPUT ;
    USE SIGNAL ;
    ANTENNAGATEAREA 0.213000 ;
    ANTENNADIFFAREA 0.434700 ;
    PORT
      LAYER met2 ;
        RECT 77.830 496.000 78.110 500.000 ;
    END
  END input_data[26]
  PIN input_data[27]
    DIRECTION INPUT ;
    USE SIGNAL ;
    ANTENNAGATEAREA 0.247500 ;
    ANTENNADIFFAREA 0.434700 ;
    PORT
      LAYER met2 ;
        RECT 79.670 496.000 79.950 500.000 ;
    END
  END input_data[27]
  PIN input_data[28]
    DIRECTION INPUT ;
    USE SIGNAL ;
    ANTENNAGATEAREA 0.196500 ;
    ANTENNADIFFAREA 0.434700 ;
    PORT
      LAYER met2 ;
        RECT 81.510 496.000 81.790 500.000 ;
    END
  END input_data[28]
  PIN input_data[29]
    DIRECTION INPUT ;
    USE SIGNAL ;
    ANTENNAGATEAREA 0.247500 ;
    ANTENNADIFFAREA 0.434700 ;
    PORT
      LAYER met2 ;
        RECT 83.350 496.000 83.630 500.000 ;
    END
  END input_data[29]
  PIN input_data[2]
    DIRECTION INPUT ;
    USE SIGNAL ;
    ANTENNAGATEAREA 0.159000 ;
    ANTENNADIFFAREA 0.434700 ;
    PORT
      LAYER met2 ;
        RECT 33.670 496.000 33.950 500.000 ;
    END
  END input_data[2]
  PIN input_data[30]
    DIRECTION INPUT ;
    USE SIGNAL ;
    ANTENNAGATEAREA 0.159000 ;
    ANTENNADIFFAREA 0.434700 ;
    PORT
      LAYER met2 ;
        RECT 85.190 496.000 85.470 500.000 ;
    END
  END input_data[30]
  PIN input_data[31]
    DIRECTION INPUT ;
    USE SIGNAL ;
    ANTENNAGATEAREA 0.126000 ;
    ANTENNADIFFAREA 0.434700 ;
    PORT
      LAYER met2 ;
        RECT 87.030 496.000 87.310 500.000 ;
    END
  END input_data[31]
  PIN input_data[32]
    DIRECTION INPUT ;
    USE SIGNAL ;
    ANTENNAGATEAREA 0.213000 ;
    ANTENNADIFFAREA 0.434700 ;
    PORT
      LAYER met2 ;
        RECT 88.870 496.000 89.150 500.000 ;
    END
  END input_data[32]
  PIN input_data[33]
    DIRECTION INPUT ;
    USE SIGNAL ;
    ANTENNAGATEAREA 0.213000 ;
    ANTENNADIFFAREA 0.434700 ;
    PORT
      LAYER met2 ;
        RECT 90.710 496.000 90.990 500.000 ;
    END
  END input_data[33]
  PIN input_data[34]
    DIRECTION INPUT ;
    USE SIGNAL ;
    ANTENNAGATEAREA 0.159000 ;
    ANTENNADIFFAREA 0.434700 ;
    PORT
      LAYER met2 ;
        RECT 92.550 496.000 92.830 500.000 ;
    END
  END input_data[34]
  PIN input_data[35]
    DIRECTION INPUT ;
    USE SIGNAL ;
    ANTENNAGATEAREA 0.213000 ;
    ANTENNADIFFAREA 0.434700 ;
    PORT
      LAYER met2 ;
        RECT 94.390 496.000 94.670 500.000 ;
    END
  END input_data[35]
  PIN input_data[36]
    DIRECTION INPUT ;
    USE SIGNAL ;
    ANTENNAGATEAREA 0.213000 ;
    ANTENNADIFFAREA 0.434700 ;
    PORT
      LAYER met2 ;
        RECT 96.230 496.000 96.510 500.000 ;
    END
  END input_data[36]
  PIN input_data[37]
    DIRECTION INPUT ;
    USE SIGNAL ;
    ANTENNAGATEAREA 0.213000 ;
    ANTENNADIFFAREA 0.434700 ;
    PORT
      LAYER met2 ;
        RECT 98.070 496.000 98.350 500.000 ;
    END
  END input_data[37]
  PIN input_data[38]
    DIRECTION INPUT ;
    USE SIGNAL ;
    ANTENNAGATEAREA 0.213000 ;
    ANTENNADIFFAREA 0.434700 ;
    PORT
      LAYER met2 ;
        RECT 99.910 496.000 100.190 500.000 ;
    END
  END input_data[38]
  PIN input_data[39]
    DIRECTION INPUT ;
    USE SIGNAL ;
    ANTENNAGATEAREA 0.126000 ;
    ANTENNADIFFAREA 0.434700 ;
    PORT
      LAYER met2 ;
        RECT 101.750 496.000 102.030 500.000 ;
    END
  END input_data[39]
  PIN input_data[3]
    DIRECTION INPUT ;
    USE SIGNAL ;
    ANTENNAGATEAREA 0.159000 ;
    ANTENNADIFFAREA 0.434700 ;
    PORT
      LAYER met2 ;
        RECT 35.510 496.000 35.790 500.000 ;
    END
  END input_data[3]
  PIN input_data[40]
    DIRECTION INPUT ;
    USE SIGNAL ;
    ANTENNAGATEAREA 0.196500 ;
    ANTENNADIFFAREA 0.434700 ;
    PORT
      LAYER met2 ;
        RECT 103.590 496.000 103.870 500.000 ;
    END
  END input_data[40]
  PIN input_data[41]
    DIRECTION INPUT ;
    USE SIGNAL ;
    ANTENNAGATEAREA 0.196500 ;
    ANTENNADIFFAREA 0.434700 ;
    PORT
      LAYER met2 ;
        RECT 105.430 496.000 105.710 500.000 ;
    END
  END input_data[41]
  PIN input_data[42]
    DIRECTION INPUT ;
    USE SIGNAL ;
    ANTENNAGATEAREA 0.196500 ;
    ANTENNADIFFAREA 0.434700 ;
    PORT
      LAYER met2 ;
        RECT 107.270 496.000 107.550 500.000 ;
    END
  END input_data[42]
  PIN input_data[43]
    DIRECTION INPUT ;
    USE SIGNAL ;
    ANTENNAGATEAREA 0.126000 ;
    ANTENNADIFFAREA 0.434700 ;
    PORT
      LAYER met2 ;
        RECT 109.110 496.000 109.390 500.000 ;
    END
  END input_data[43]
  PIN input_data[44]
    DIRECTION INPUT ;
    USE SIGNAL ;
    ANTENNAGATEAREA 0.247500 ;
    ANTENNADIFFAREA 0.434700 ;
    PORT
      LAYER met2 ;
        RECT 110.950 496.000 111.230 500.000 ;
    END
  END input_data[44]
  PIN input_data[45]
    DIRECTION INPUT ;
    USE SIGNAL ;
    ANTENNAGATEAREA 0.213000 ;
    ANTENNADIFFAREA 0.434700 ;
    PORT
      LAYER met2 ;
        RECT 112.790 496.000 113.070 500.000 ;
    END
  END input_data[45]
  PIN input_data[46]
    DIRECTION INPUT ;
    USE SIGNAL ;
    ANTENNAGATEAREA 0.196500 ;
    ANTENNADIFFAREA 0.434700 ;
    PORT
      LAYER met2 ;
        RECT 114.630 496.000 114.910 500.000 ;
    END
  END input_data[46]
  PIN input_data[47]
    DIRECTION INPUT ;
    USE SIGNAL ;
    ANTENNAGATEAREA 0.196500 ;
    ANTENNADIFFAREA 0.434700 ;
    PORT
      LAYER met2 ;
        RECT 116.470 496.000 116.750 500.000 ;
    END
  END input_data[47]
  PIN input_data[48]
    DIRECTION INPUT ;
    USE SIGNAL ;
    ANTENNAGATEAREA 0.196500 ;
    ANTENNADIFFAREA 0.434700 ;
    PORT
      LAYER met2 ;
        RECT 118.310 496.000 118.590 500.000 ;
    END
  END input_data[48]
  PIN input_data[49]
    DIRECTION INPUT ;
    USE SIGNAL ;
    ANTENNAGATEAREA 0.126000 ;
    ANTENNADIFFAREA 0.434700 ;
    PORT
      LAYER met2 ;
        RECT 120.150 496.000 120.430 500.000 ;
    END
  END input_data[49]
  PIN input_data[4]
    DIRECTION INPUT ;
    USE SIGNAL ;
    ANTENNAGATEAREA 0.159000 ;
    ANTENNADIFFAREA 0.434700 ;
    PORT
      LAYER met2 ;
        RECT 37.350 496.000 37.630 500.000 ;
    END
  END input_data[4]
  PIN input_data[50]
    DIRECTION INPUT ;
    USE SIGNAL ;
    ANTENNAGATEAREA 0.196500 ;
    ANTENNADIFFAREA 0.434700 ;
    PORT
      LAYER met2 ;
        RECT 121.990 496.000 122.270 500.000 ;
    END
  END input_data[50]
  PIN input_data[51]
    DIRECTION INPUT ;
    USE SIGNAL ;
    ANTENNAGATEAREA 0.196500 ;
    ANTENNADIFFAREA 0.434700 ;
    PORT
      LAYER met2 ;
        RECT 123.830 496.000 124.110 500.000 ;
    END
  END input_data[51]
  PIN input_data[52]
    DIRECTION INPUT ;
    USE SIGNAL ;
    ANTENNAGATEAREA 0.196500 ;
    ANTENNADIFFAREA 0.434700 ;
    PORT
      LAYER met2 ;
        RECT 125.670 496.000 125.950 500.000 ;
    END
  END input_data[52]
  PIN input_data[53]
    DIRECTION INPUT ;
    USE SIGNAL ;
    ANTENNAGATEAREA 0.126000 ;
    ANTENNADIFFAREA 0.434700 ;
    PORT
      LAYER met2 ;
        RECT 127.510 496.000 127.790 500.000 ;
    END
  END input_data[53]
  PIN input_data[54]
    DIRECTION INPUT ;
    USE SIGNAL ;
    ANTENNAGATEAREA 0.213000 ;
    ANTENNADIFFAREA 0.434700 ;
    PORT
      LAYER met2 ;
        RECT 129.350 496.000 129.630 500.000 ;
    END
  END input_data[54]
  PIN input_data[55]
    DIRECTION INPUT ;
    USE SIGNAL ;
    ANTENNAGATEAREA 0.196500 ;
    ANTENNADIFFAREA 0.434700 ;
    PORT
      LAYER met2 ;
        RECT 131.190 496.000 131.470 500.000 ;
    END
  END input_data[55]
  PIN input_data[56]
    DIRECTION INPUT ;
    USE SIGNAL ;
    ANTENNAGATEAREA 0.213000 ;
    ANTENNADIFFAREA 0.434700 ;
    PORT
      LAYER met2 ;
        RECT 133.030 496.000 133.310 500.000 ;
    END
  END input_data[56]
  PIN input_data[57]
    DIRECTION INPUT ;
    USE SIGNAL ;
    ANTENNAGATEAREA 0.126000 ;
    ANTENNADIFFAREA 0.434700 ;
    PORT
      LAYER met2 ;
        RECT 134.870 496.000 135.150 500.000 ;
    END
  END input_data[57]
  PIN input_data[58]
    DIRECTION INPUT ;
    USE SIGNAL ;
    ANTENNAGATEAREA 0.213000 ;
    ANTENNADIFFAREA 0.434700 ;
    PORT
      LAYER met2 ;
        RECT 136.710 496.000 136.990 500.000 ;
    END
  END input_data[58]
  PIN input_data[59]
    DIRECTION INPUT ;
    USE SIGNAL ;
    ANTENNAGATEAREA 0.247500 ;
    ANTENNADIFFAREA 0.434700 ;
    PORT
      LAYER met2 ;
        RECT 138.550 496.000 138.830 500.000 ;
    END
  END input_data[59]
  PIN input_data[5]
    DIRECTION INPUT ;
    USE SIGNAL ;
    ANTENNAGATEAREA 0.159000 ;
    ANTENNADIFFAREA 0.434700 ;
    PORT
      LAYER met2 ;
        RECT 39.190 496.000 39.470 500.000 ;
    END
  END input_data[5]
  PIN input_data[60]
    DIRECTION INPUT ;
    USE SIGNAL ;
    ANTENNAGATEAREA 0.159000 ;
    ANTENNADIFFAREA 0.434700 ;
    PORT
      LAYER met2 ;
        RECT 140.390 496.000 140.670 500.000 ;
    END
  END input_data[60]
  PIN input_data[61]
    DIRECTION INPUT ;
    USE SIGNAL ;
    ANTENNAGATEAREA 0.213000 ;
    ANTENNADIFFAREA 0.434700 ;
    PORT
      LAYER met2 ;
        RECT 142.230 496.000 142.510 500.000 ;
    END
  END input_data[61]
  PIN input_data[62]
    DIRECTION INPUT ;
    USE SIGNAL ;
    ANTENNAGATEAREA 0.213000 ;
    ANTENNADIFFAREA 0.434700 ;
    PORT
      LAYER met2 ;
        RECT 144.070 496.000 144.350 500.000 ;
    END
  END input_data[62]
  PIN input_data[63]
    DIRECTION INPUT ;
    USE SIGNAL ;
    PORT
      LAYER met2 ;
        RECT 145.910 496.000 146.190 500.000 ;
    END
  END input_data[63]
  PIN input_data[64]
    DIRECTION INPUT ;
    USE SIGNAL ;
    ANTENNAGATEAREA 0.213000 ;
    ANTENNADIFFAREA 0.434700 ;
    PORT
      LAYER met2 ;
        RECT 147.750 496.000 148.030 500.000 ;
    END
  END input_data[64]
  PIN input_data[65]
    DIRECTION INPUT ;
    USE SIGNAL ;
    ANTENNAGATEAREA 0.247500 ;
    ANTENNADIFFAREA 0.434700 ;
    PORT
      LAYER met2 ;
        RECT 149.590 496.000 149.870 500.000 ;
    END
  END input_data[65]
  PIN input_data[66]
    DIRECTION INPUT ;
    USE SIGNAL ;
    ANTENNAGATEAREA 0.196500 ;
    ANTENNADIFFAREA 0.434700 ;
    PORT
      LAYER met2 ;
        RECT 151.430 496.000 151.710 500.000 ;
    END
  END input_data[66]
  PIN input_data[67]
    DIRECTION INPUT ;
    USE SIGNAL ;
    ANTENNAGATEAREA 0.196500 ;
    ANTENNADIFFAREA 0.434700 ;
    PORT
      LAYER met2 ;
        RECT 153.270 496.000 153.550 500.000 ;
    END
  END input_data[67]
  PIN input_data[68]
    DIRECTION INPUT ;
    USE SIGNAL ;
    ANTENNAGATEAREA 0.213000 ;
    ANTENNADIFFAREA 0.434700 ;
    PORT
      LAYER met2 ;
        RECT 155.110 496.000 155.390 500.000 ;
    END
  END input_data[68]
  PIN input_data[69]
    DIRECTION INPUT ;
    USE SIGNAL ;
    ANTENNAGATEAREA 0.196500 ;
    ANTENNADIFFAREA 0.434700 ;
    PORT
      LAYER met2 ;
        RECT 156.950 496.000 157.230 500.000 ;
    END
  END input_data[69]
  PIN input_data[6]
    DIRECTION INPUT ;
    USE SIGNAL ;
    ANTENNAGATEAREA 0.159000 ;
    ANTENNADIFFAREA 0.434700 ;
    PORT
      LAYER met2 ;
        RECT 41.030 496.000 41.310 500.000 ;
    END
  END input_data[6]
  PIN input_data[70]
    DIRECTION INPUT ;
    USE SIGNAL ;
    ANTENNAGATEAREA 0.196500 ;
    ANTENNADIFFAREA 0.434700 ;
    PORT
      LAYER met2 ;
        RECT 158.790 496.000 159.070 500.000 ;
    END
  END input_data[70]
  PIN input_data[71]
    DIRECTION INPUT ;
    USE SIGNAL ;
    ANTENNAGATEAREA 0.196500 ;
    ANTENNADIFFAREA 0.434700 ;
    PORT
      LAYER met2 ;
        RECT 160.630 496.000 160.910 500.000 ;
    END
  END input_data[71]
  PIN input_data[72]
    DIRECTION INPUT ;
    USE SIGNAL ;
    ANTENNAGATEAREA 0.196500 ;
    ANTENNADIFFAREA 0.434700 ;
    PORT
      LAYER met2 ;
        RECT 162.470 496.000 162.750 500.000 ;
    END
  END input_data[72]
  PIN input_data[73]
    DIRECTION INPUT ;
    USE SIGNAL ;
    ANTENNAGATEAREA 0.213000 ;
    ANTENNADIFFAREA 0.434700 ;
    PORT
      LAYER met2 ;
        RECT 164.310 496.000 164.590 500.000 ;
    END
  END input_data[73]
  PIN input_data[74]
    DIRECTION INPUT ;
    USE SIGNAL ;
    ANTENNAGATEAREA 0.196500 ;
    ANTENNADIFFAREA 0.434700 ;
    PORT
      LAYER met2 ;
        RECT 166.150 496.000 166.430 500.000 ;
    END
  END input_data[74]
  PIN input_data[75]
    DIRECTION INPUT ;
    USE SIGNAL ;
    ANTENNAGATEAREA 0.196500 ;
    ANTENNADIFFAREA 0.434700 ;
    PORT
      LAYER met2 ;
        RECT 167.990 496.000 168.270 500.000 ;
    END
  END input_data[75]
  PIN input_data[76]
    DIRECTION INPUT ;
    USE SIGNAL ;
    ANTENNAGATEAREA 0.196500 ;
    ANTENNADIFFAREA 0.434700 ;
    PORT
      LAYER met2 ;
        RECT 169.830 496.000 170.110 500.000 ;
    END
  END input_data[76]
  PIN input_data[77]
    DIRECTION INPUT ;
    USE SIGNAL ;
    ANTENNAGATEAREA 0.213000 ;
    ANTENNADIFFAREA 0.434700 ;
    PORT
      LAYER met2 ;
        RECT 171.670 496.000 171.950 500.000 ;
    END
  END input_data[77]
  PIN input_data[78]
    DIRECTION INPUT ;
    USE SIGNAL ;
    ANTENNAGATEAREA 0.196500 ;
    ANTENNADIFFAREA 0.434700 ;
    PORT
      LAYER met2 ;
        RECT 173.510 496.000 173.790 500.000 ;
    END
  END input_data[78]
  PIN input_data[79]
    DIRECTION INPUT ;
    USE SIGNAL ;
    PORT
      LAYER met2 ;
        RECT 175.350 496.000 175.630 500.000 ;
    END
  END input_data[79]
  PIN input_data[7]
    DIRECTION INPUT ;
    USE SIGNAL ;
    ANTENNAGATEAREA 0.213000 ;
    ANTENNADIFFAREA 0.434700 ;
    PORT
      LAYER met2 ;
        RECT 42.870 496.000 43.150 500.000 ;
    END
  END input_data[7]
  PIN input_data[80]
    DIRECTION INPUT ;
    USE SIGNAL ;
    ANTENNAGATEAREA 0.213000 ;
    ANTENNADIFFAREA 0.434700 ;
    PORT
      LAYER met2 ;
        RECT 177.190 496.000 177.470 500.000 ;
    END
  END input_data[80]
  PIN input_data[81]
    DIRECTION INPUT ;
    USE SIGNAL ;
    ANTENNAGATEAREA 0.159000 ;
    ANTENNADIFFAREA 0.434700 ;
    PORT
      LAYER met2 ;
        RECT 179.030 496.000 179.310 500.000 ;
    END
  END input_data[81]
  PIN input_data[82]
    DIRECTION INPUT ;
    USE SIGNAL ;
    ANTENNAGATEAREA 0.159000 ;
    ANTENNADIFFAREA 0.434700 ;
    PORT
      LAYER met2 ;
        RECT 180.870 496.000 181.150 500.000 ;
    END
  END input_data[82]
  PIN input_data[83]
    DIRECTION INPUT ;
    USE SIGNAL ;
    ANTENNAGATEAREA 0.159000 ;
    ANTENNADIFFAREA 0.434700 ;
    PORT
      LAYER met2 ;
        RECT 182.710 496.000 182.990 500.000 ;
    END
  END input_data[83]
  PIN input_data[84]
    DIRECTION INPUT ;
    USE SIGNAL ;
    ANTENNAGATEAREA 0.159000 ;
    ANTENNADIFFAREA 0.434700 ;
    PORT
      LAYER met2 ;
        RECT 184.550 496.000 184.830 500.000 ;
    END
  END input_data[84]
  PIN input_data[85]
    DIRECTION INPUT ;
    USE SIGNAL ;
    ANTENNAGATEAREA 0.213000 ;
    ANTENNADIFFAREA 0.434700 ;
    PORT
      LAYER met2 ;
        RECT 186.390 496.000 186.670 500.000 ;
    END
  END input_data[85]
  PIN input_data[86]
    DIRECTION INPUT ;
    USE SIGNAL ;
    ANTENNAGATEAREA 0.247500 ;
    ANTENNADIFFAREA 0.434700 ;
    PORT
      LAYER met2 ;
        RECT 188.230 496.000 188.510 500.000 ;
    END
  END input_data[86]
  PIN input_data[87]
    DIRECTION INPUT ;
    USE SIGNAL ;
    ANTENNAGATEAREA 0.247500 ;
    ANTENNADIFFAREA 0.434700 ;
    PORT
      LAYER met2 ;
        RECT 190.070 496.000 190.350 500.000 ;
    END
  END input_data[87]
  PIN input_data[88]
    DIRECTION INPUT ;
    USE SIGNAL ;
    ANTENNAGATEAREA 0.247500 ;
    ANTENNADIFFAREA 0.434700 ;
    PORT
      LAYER met2 ;
        RECT 191.910 496.000 192.190 500.000 ;
    END
  END input_data[88]
  PIN input_data[89]
    DIRECTION INPUT ;
    USE SIGNAL ;
    ANTENNAGATEAREA 0.159000 ;
    ANTENNADIFFAREA 0.434700 ;
    PORT
      LAYER met2 ;
        RECT 193.750 496.000 194.030 500.000 ;
    END
  END input_data[89]
  PIN input_data[8]
    DIRECTION INPUT ;
    USE SIGNAL ;
    ANTENNAGATEAREA 0.159000 ;
    ANTENNADIFFAREA 0.434700 ;
    PORT
      LAYER met2 ;
        RECT 44.710 496.000 44.990 500.000 ;
    END
  END input_data[8]
  PIN input_data[90]
    DIRECTION INPUT ;
    USE SIGNAL ;
    ANTENNAGATEAREA 0.159000 ;
    ANTENNADIFFAREA 0.434700 ;
    PORT
      LAYER met2 ;
        RECT 195.590 496.000 195.870 500.000 ;
    END
  END input_data[90]
  PIN input_data[91]
    DIRECTION INPUT ;
    USE SIGNAL ;
    ANTENNAGATEAREA 0.247500 ;
    ANTENNADIFFAREA 0.434700 ;
    PORT
      LAYER met2 ;
        RECT 197.430 496.000 197.710 500.000 ;
    END
  END input_data[91]
  PIN input_data[92]
    DIRECTION INPUT ;
    USE SIGNAL ;
    ANTENNAGATEAREA 0.213000 ;
    ANTENNADIFFAREA 0.434700 ;
    PORT
      LAYER met2 ;
        RECT 199.270 496.000 199.550 500.000 ;
    END
  END input_data[92]
  PIN input_data[93]
    DIRECTION INPUT ;
    USE SIGNAL ;
    ANTENNAGATEAREA 0.247500 ;
    ANTENNADIFFAREA 0.434700 ;
    PORT
      LAYER met2 ;
        RECT 201.110 496.000 201.390 500.000 ;
    END
  END input_data[93]
  PIN input_data[94]
    DIRECTION INPUT ;
    USE SIGNAL ;
    ANTENNAGATEAREA 0.213000 ;
    ANTENNADIFFAREA 0.434700 ;
    PORT
      LAYER met2 ;
        RECT 202.950 496.000 203.230 500.000 ;
    END
  END input_data[94]
  PIN input_data[95]
    DIRECTION INPUT ;
    USE SIGNAL ;
    ANTENNAGATEAREA 0.196500 ;
    ANTENNADIFFAREA 0.434700 ;
    PORT
      LAYER met2 ;
        RECT 204.790 496.000 205.070 500.000 ;
    END
  END input_data[95]
  PIN input_data[96]
    DIRECTION INPUT ;
    USE SIGNAL ;
    ANTENNAGATEAREA 0.196500 ;
    ANTENNADIFFAREA 0.434700 ;
    PORT
      LAYER met2 ;
        RECT 206.630 496.000 206.910 500.000 ;
    END
  END input_data[96]
  PIN input_data[97]
    DIRECTION INPUT ;
    USE SIGNAL ;
    ANTENNAGATEAREA 0.196500 ;
    ANTENNADIFFAREA 0.434700 ;
    PORT
      LAYER met2 ;
        RECT 208.470 496.000 208.750 500.000 ;
    END
  END input_data[97]
  PIN input_data[98]
    DIRECTION INPUT ;
    USE SIGNAL ;
    ANTENNAGATEAREA 0.213000 ;
    ANTENNADIFFAREA 0.434700 ;
    PORT
      LAYER met2 ;
        RECT 210.310 496.000 210.590 500.000 ;
    END
  END input_data[98]
  PIN input_data[99]
    DIRECTION INPUT ;
    USE SIGNAL ;
    ANTENNAGATEAREA 0.196500 ;
    ANTENNADIFFAREA 0.434700 ;
    PORT
      LAYER met2 ;
        RECT 212.150 496.000 212.430 500.000 ;
    END
  END input_data[99]
  PIN input_data[9]
    DIRECTION INPUT ;
    USE SIGNAL ;
    ANTENNAGATEAREA 0.213000 ;
    ANTENNADIFFAREA 0.434700 ;
    PORT
      LAYER met2 ;
        RECT 46.550 496.000 46.830 500.000 ;
    END
  END input_data[9]
  PIN output_high[0]
    DIRECTION OUTPUT ;
    USE SIGNAL ;
    ANTENNADIFFAREA 0.795200 ;
    PORT
      LAYER met3 ;
        RECT 0.000 15.000 4.000 15.600 ;
    END
  END output_high[0]
  PIN output_high[10]
    DIRECTION OUTPUT ;
    USE SIGNAL ;
    ANTENNADIFFAREA 0.795200 ;
    PORT
      LAYER met3 ;
        RECT 0.000 327.800 4.000 328.400 ;
    END
  END output_high[10]
  PIN output_high[11]
    DIRECTION OUTPUT ;
    USE SIGNAL ;
    ANTENNADIFFAREA 0.795200 ;
    PORT
      LAYER met3 ;
        RECT 0.000 359.080 4.000 359.680 ;
    END
  END output_high[11]
  PIN output_high[12]
    DIRECTION OUTPUT ;
    USE SIGNAL ;
    ANTENNADIFFAREA 0.795200 ;
    PORT
      LAYER met3 ;
        RECT 0.000 390.360 4.000 390.960 ;
    END
  END output_high[12]
  PIN output_high[13]
    DIRECTION OUTPUT ;
    USE SIGNAL ;
    ANTENNADIFFAREA 0.795200 ;
    PORT
      LAYER met3 ;
        RECT 0.000 421.640 4.000 422.240 ;
    END
  END output_high[13]
  PIN output_high[14]
    DIRECTION OUTPUT ;
    USE SIGNAL ;
    ANTENNADIFFAREA 0.795200 ;
    PORT
      LAYER met3 ;
        RECT 0.000 452.920 4.000 453.520 ;
    END
  END output_high[14]
  PIN output_high[15]
    DIRECTION OUTPUT ;
    USE SIGNAL ;
    ANTENNADIFFAREA 0.795200 ;
    PORT
      LAYER met3 ;
        RECT 0.000 484.200 4.000 484.800 ;
    END
  END output_high[15]
  PIN output_high[1]
    DIRECTION OUTPUT ;
    USE SIGNAL ;
    ANTENNADIFFAREA 0.795200 ;
    PORT
      LAYER met3 ;
        RECT 0.000 46.280 4.000 46.880 ;
    END
  END output_high[1]
  PIN output_high[2]
    DIRECTION OUTPUT ;
    USE SIGNAL ;
    ANTENNADIFFAREA 0.795200 ;
    PORT
      LAYER met3 ;
        RECT 0.000 77.560 4.000 78.160 ;
    END
  END output_high[2]
  PIN output_high[3]
    DIRECTION OUTPUT ;
    USE SIGNAL ;
    ANTENNADIFFAREA 0.795200 ;
    PORT
      LAYER met3 ;
        RECT 0.000 108.840 4.000 109.440 ;
    END
  END output_high[3]
  PIN output_high[4]
    DIRECTION OUTPUT ;
    USE SIGNAL ;
    ANTENNADIFFAREA 0.795200 ;
    PORT
      LAYER met3 ;
        RECT 0.000 140.120 4.000 140.720 ;
    END
  END output_high[4]
  PIN output_high[5]
    DIRECTION OUTPUT ;
    USE SIGNAL ;
    ANTENNADIFFAREA 0.795200 ;
    PORT
      LAYER met3 ;
        RECT 0.000 171.400 4.000 172.000 ;
    END
  END output_high[5]
  PIN output_high[6]
    DIRECTION OUTPUT ;
    USE SIGNAL ;
    ANTENNADIFFAREA 0.795200 ;
    PORT
      LAYER met3 ;
        RECT 0.000 202.680 4.000 203.280 ;
    END
  END output_high[6]
  PIN output_high[7]
    DIRECTION OUTPUT ;
    USE SIGNAL ;
    ANTENNADIFFAREA 0.795200 ;
    PORT
      LAYER met3 ;
        RECT 0.000 233.960 4.000 234.560 ;
    END
  END output_high[7]
  PIN output_high[8]
    DIRECTION OUTPUT ;
    USE SIGNAL ;
    ANTENNADIFFAREA 0.795200 ;
    PORT
      LAYER met3 ;
        RECT 0.000 265.240 4.000 265.840 ;
    END
  END output_high[8]
  PIN output_high[9]
    DIRECTION OUTPUT ;
    USE SIGNAL ;
    ANTENNADIFFAREA 0.795200 ;
    PORT
      LAYER met3 ;
        RECT 0.000 296.520 4.000 297.120 ;
    END
  END output_high[9]
  PIN tap[0]
    DIRECTION INPUT ;
    USE SIGNAL ;
    ANTENNAGATEAREA 0.213000 ;
    ANTENNADIFFAREA 0.434700 ;
    PORT
      LAYER met2 ;
        RECT 62.650 0.000 62.930 4.000 ;
    END
  END tap[0]
  PIN tap[1]
    DIRECTION INPUT ;
    USE SIGNAL ;
    ANTENNAGATEAREA 0.213000 ;
    ANTENNADIFFAREA 0.434700 ;
    PORT
      LAYER met2 ;
        RECT 187.310 0.000 187.590 4.000 ;
    END
  END tap[1]
  PIN tap[2]
    DIRECTION INPUT ;
    USE SIGNAL ;
    ANTENNAGATEAREA 0.213000 ;
    ANTENNADIFFAREA 0.434700 ;
    PORT
      LAYER met2 ;
        RECT 311.970 0.000 312.250 4.000 ;
    END
  END tap[2]
  PIN tap[3]
    DIRECTION INPUT ;
    USE SIGNAL ;
    ANTENNAGATEAREA 0.247500 ;
    ANTENNADIFFAREA 0.434700 ;
    PORT
      LAYER met2 ;
        RECT 436.630 0.000 436.910 4.000 ;
    END
  END tap[3]
  OBS
      LAYER li1 ;
        RECT 50.140 51.595 449.880 448.885 ;
      LAYER met1 ;
        RECT 17.090 51.440 466.370 497.040 ;
      LAYER met2 ;
        RECT 17.110 495.720 29.710 498.170 ;
        RECT 30.550 495.720 31.550 498.170 ;
        RECT 32.390 495.720 33.390 498.170 ;
        RECT 34.230 495.720 35.230 498.170 ;
        RECT 36.070 495.720 37.070 498.170 ;
        RECT 37.910 495.720 38.910 498.170 ;
        RECT 39.750 495.720 40.750 498.170 ;
        RECT 41.590 495.720 42.590 498.170 ;
        RECT 43.430 495.720 44.430 498.170 ;
        RECT 45.270 495.720 46.270 498.170 ;
        RECT 47.110 495.720 48.110 498.170 ;
        RECT 48.950 495.720 49.950 498.170 ;
        RECT 50.790 495.720 51.790 498.170 ;
        RECT 52.630 495.720 53.630 498.170 ;
        RECT 54.470 495.720 55.470 498.170 ;
        RECT 56.310 495.720 57.310 498.170 ;
        RECT 58.150 495.720 59.150 498.170 ;
        RECT 59.990 495.720 60.990 498.170 ;
        RECT 61.830 495.720 62.830 498.170 ;
        RECT 63.670 495.720 64.670 498.170 ;
        RECT 65.510 495.720 66.510 498.170 ;
        RECT 67.350 495.720 68.350 498.170 ;
        RECT 69.190 495.720 70.190 498.170 ;
        RECT 71.030 495.720 72.030 498.170 ;
        RECT 72.870 495.720 73.870 498.170 ;
        RECT 74.710 495.720 75.710 498.170 ;
        RECT 76.550 495.720 77.550 498.170 ;
        RECT 78.390 495.720 79.390 498.170 ;
        RECT 80.230 495.720 81.230 498.170 ;
        RECT 82.070 495.720 83.070 498.170 ;
        RECT 83.910 495.720 84.910 498.170 ;
        RECT 85.750 495.720 86.750 498.170 ;
        RECT 87.590 495.720 88.590 498.170 ;
        RECT 89.430 495.720 90.430 498.170 ;
        RECT 91.270 495.720 92.270 498.170 ;
        RECT 93.110 495.720 94.110 498.170 ;
        RECT 94.950 495.720 95.950 498.170 ;
        RECT 96.790 495.720 97.790 498.170 ;
        RECT 98.630 495.720 99.630 498.170 ;
        RECT 100.470 495.720 101.470 498.170 ;
        RECT 102.310 495.720 103.310 498.170 ;
        RECT 104.150 495.720 105.150 498.170 ;
        RECT 105.990 495.720 106.990 498.170 ;
        RECT 107.830 495.720 108.830 498.170 ;
        RECT 109.670 495.720 110.670 498.170 ;
        RECT 111.510 495.720 112.510 498.170 ;
        RECT 113.350 495.720 114.350 498.170 ;
        RECT 115.190 495.720 116.190 498.170 ;
        RECT 117.030 495.720 118.030 498.170 ;
        RECT 118.870 495.720 119.870 498.170 ;
        RECT 120.710 495.720 121.710 498.170 ;
        RECT 122.550 495.720 123.550 498.170 ;
        RECT 124.390 495.720 125.390 498.170 ;
        RECT 126.230 495.720 127.230 498.170 ;
        RECT 128.070 495.720 129.070 498.170 ;
        RECT 129.910 495.720 130.910 498.170 ;
        RECT 131.750 495.720 132.750 498.170 ;
        RECT 133.590 495.720 134.590 498.170 ;
        RECT 135.430 495.720 136.430 498.170 ;
        RECT 137.270 495.720 138.270 498.170 ;
        RECT 139.110 495.720 140.110 498.170 ;
        RECT 140.950 495.720 141.950 498.170 ;
        RECT 142.790 495.720 143.790 498.170 ;
        RECT 144.630 495.720 145.630 498.170 ;
        RECT 146.470 495.720 147.470 498.170 ;
        RECT 148.310 495.720 149.310 498.170 ;
        RECT 150.150 495.720 151.150 498.170 ;
        RECT 151.990 495.720 152.990 498.170 ;
        RECT 153.830 495.720 154.830 498.170 ;
        RECT 155.670 495.720 156.670 498.170 ;
        RECT 157.510 495.720 158.510 498.170 ;
        RECT 159.350 495.720 160.350 498.170 ;
        RECT 161.190 495.720 162.190 498.170 ;
        RECT 163.030 495.720 164.030 498.170 ;
        RECT 164.870 495.720 165.870 498.170 ;
        RECT 166.710 495.720 167.710 498.170 ;
        RECT 168.550 495.720 169.550 498.170 ;
        RECT 170.390 495.720 171.390 498.170 ;
        RECT 172.230 495.720 173.230 498.170 ;
        RECT 174.070 495.720 175.070 498.170 ;
        RECT 175.910 495.720 176.910 498.170 ;
        RECT 177.750 495.720 178.750 498.170 ;
        RECT 179.590 495.720 180.590 498.170 ;
        RECT 181.430 495.720 182.430 498.170 ;
        RECT 183.270 495.720 184.270 498.170 ;
        RECT 185.110 495.720 186.110 498.170 ;
        RECT 186.950 495.720 187.950 498.170 ;
        RECT 188.790 495.720 189.790 498.170 ;
        RECT 190.630 495.720 191.630 498.170 ;
        RECT 192.470 495.720 193.470 498.170 ;
        RECT 194.310 495.720 195.310 498.170 ;
        RECT 196.150 495.720 197.150 498.170 ;
        RECT 197.990 495.720 198.990 498.170 ;
        RECT 199.830 495.720 200.830 498.170 ;
        RECT 201.670 495.720 202.670 498.170 ;
        RECT 203.510 495.720 204.510 498.170 ;
        RECT 205.350 495.720 206.350 498.170 ;
        RECT 207.190 495.720 208.190 498.170 ;
        RECT 209.030 495.720 210.030 498.170 ;
        RECT 210.870 495.720 211.870 498.170 ;
        RECT 212.710 495.720 213.710 498.170 ;
        RECT 214.550 495.720 215.550 498.170 ;
        RECT 216.390 495.720 217.390 498.170 ;
        RECT 218.230 495.720 219.230 498.170 ;
        RECT 220.070 495.720 221.070 498.170 ;
        RECT 221.910 495.720 222.910 498.170 ;
        RECT 223.750 495.720 224.750 498.170 ;
        RECT 225.590 495.720 226.590 498.170 ;
        RECT 227.430 495.720 228.430 498.170 ;
        RECT 229.270 495.720 230.270 498.170 ;
        RECT 231.110 495.720 232.110 498.170 ;
        RECT 232.950 495.720 233.950 498.170 ;
        RECT 234.790 495.720 235.790 498.170 ;
        RECT 236.630 495.720 237.630 498.170 ;
        RECT 238.470 495.720 239.470 498.170 ;
        RECT 240.310 495.720 241.310 498.170 ;
        RECT 242.150 495.720 243.150 498.170 ;
        RECT 243.990 495.720 244.990 498.170 ;
        RECT 245.830 495.720 246.830 498.170 ;
        RECT 247.670 495.720 248.670 498.170 ;
        RECT 249.510 495.720 250.510 498.170 ;
        RECT 251.350 495.720 252.350 498.170 ;
        RECT 253.190 495.720 254.190 498.170 ;
        RECT 255.030 495.720 256.030 498.170 ;
        RECT 256.870 495.720 257.870 498.170 ;
        RECT 258.710 495.720 259.710 498.170 ;
        RECT 260.550 495.720 261.550 498.170 ;
        RECT 262.390 495.720 263.390 498.170 ;
        RECT 264.230 495.720 265.230 498.170 ;
        RECT 266.070 495.720 267.070 498.170 ;
        RECT 267.910 495.720 268.910 498.170 ;
        RECT 269.750 495.720 270.750 498.170 ;
        RECT 271.590 495.720 272.590 498.170 ;
        RECT 273.430 495.720 274.430 498.170 ;
        RECT 275.270 495.720 276.270 498.170 ;
        RECT 277.110 495.720 278.110 498.170 ;
        RECT 278.950 495.720 279.950 498.170 ;
        RECT 280.790 495.720 281.790 498.170 ;
        RECT 282.630 495.720 283.630 498.170 ;
        RECT 284.470 495.720 285.470 498.170 ;
        RECT 286.310 495.720 287.310 498.170 ;
        RECT 288.150 495.720 289.150 498.170 ;
        RECT 289.990 495.720 290.990 498.170 ;
        RECT 291.830 495.720 292.830 498.170 ;
        RECT 293.670 495.720 294.670 498.170 ;
        RECT 295.510 495.720 296.510 498.170 ;
        RECT 297.350 495.720 298.350 498.170 ;
        RECT 299.190 495.720 300.190 498.170 ;
        RECT 301.030 495.720 302.030 498.170 ;
        RECT 302.870 495.720 303.870 498.170 ;
        RECT 304.710 495.720 305.710 498.170 ;
        RECT 306.550 495.720 307.550 498.170 ;
        RECT 308.390 495.720 309.390 498.170 ;
        RECT 310.230 495.720 311.230 498.170 ;
        RECT 312.070 495.720 313.070 498.170 ;
        RECT 313.910 495.720 314.910 498.170 ;
        RECT 315.750 495.720 316.750 498.170 ;
        RECT 317.590 495.720 318.590 498.170 ;
        RECT 319.430 495.720 320.430 498.170 ;
        RECT 321.270 495.720 322.270 498.170 ;
        RECT 323.110 495.720 324.110 498.170 ;
        RECT 324.950 495.720 325.950 498.170 ;
        RECT 326.790 495.720 327.790 498.170 ;
        RECT 328.630 495.720 329.630 498.170 ;
        RECT 330.470 495.720 331.470 498.170 ;
        RECT 332.310 495.720 333.310 498.170 ;
        RECT 334.150 495.720 335.150 498.170 ;
        RECT 335.990 495.720 336.990 498.170 ;
        RECT 337.830 495.720 338.830 498.170 ;
        RECT 339.670 495.720 340.670 498.170 ;
        RECT 341.510 495.720 342.510 498.170 ;
        RECT 343.350 495.720 344.350 498.170 ;
        RECT 345.190 495.720 346.190 498.170 ;
        RECT 347.030 495.720 348.030 498.170 ;
        RECT 348.870 495.720 349.870 498.170 ;
        RECT 350.710 495.720 351.710 498.170 ;
        RECT 352.550 495.720 353.550 498.170 ;
        RECT 354.390 495.720 355.390 498.170 ;
        RECT 356.230 495.720 357.230 498.170 ;
        RECT 358.070 495.720 359.070 498.170 ;
        RECT 359.910 495.720 360.910 498.170 ;
        RECT 361.750 495.720 362.750 498.170 ;
        RECT 363.590 495.720 364.590 498.170 ;
        RECT 365.430 495.720 366.430 498.170 ;
        RECT 367.270 495.720 368.270 498.170 ;
        RECT 369.110 495.720 370.110 498.170 ;
        RECT 370.950 495.720 371.950 498.170 ;
        RECT 372.790 495.720 373.790 498.170 ;
        RECT 374.630 495.720 375.630 498.170 ;
        RECT 376.470 495.720 377.470 498.170 ;
        RECT 378.310 495.720 379.310 498.170 ;
        RECT 380.150 495.720 381.150 498.170 ;
        RECT 381.990 495.720 382.990 498.170 ;
        RECT 383.830 495.720 384.830 498.170 ;
        RECT 385.670 495.720 386.670 498.170 ;
        RECT 387.510 495.720 388.510 498.170 ;
        RECT 389.350 495.720 390.350 498.170 ;
        RECT 391.190 495.720 392.190 498.170 ;
        RECT 393.030 495.720 394.030 498.170 ;
        RECT 394.870 495.720 395.870 498.170 ;
        RECT 396.710 495.720 397.710 498.170 ;
        RECT 398.550 495.720 399.550 498.170 ;
        RECT 400.390 495.720 401.390 498.170 ;
        RECT 402.230 495.720 403.230 498.170 ;
        RECT 404.070 495.720 405.070 498.170 ;
        RECT 405.910 495.720 406.910 498.170 ;
        RECT 407.750 495.720 408.750 498.170 ;
        RECT 409.590 495.720 410.590 498.170 ;
        RECT 411.430 495.720 412.430 498.170 ;
        RECT 413.270 495.720 414.270 498.170 ;
        RECT 415.110 495.720 416.110 498.170 ;
        RECT 416.950 495.720 417.950 498.170 ;
        RECT 418.790 495.720 419.790 498.170 ;
        RECT 420.630 495.720 421.630 498.170 ;
        RECT 422.470 495.720 423.470 498.170 ;
        RECT 424.310 495.720 425.310 498.170 ;
        RECT 426.150 495.720 427.150 498.170 ;
        RECT 427.990 495.720 428.990 498.170 ;
        RECT 429.830 495.720 430.830 498.170 ;
        RECT 431.670 495.720 432.670 498.170 ;
        RECT 433.510 495.720 434.510 498.170 ;
        RECT 435.350 495.720 436.350 498.170 ;
        RECT 437.190 495.720 438.190 498.170 ;
        RECT 439.030 495.720 440.030 498.170 ;
        RECT 440.870 495.720 441.870 498.170 ;
        RECT 442.710 495.720 443.710 498.170 ;
        RECT 444.550 495.720 445.550 498.170 ;
        RECT 446.390 495.720 447.390 498.170 ;
        RECT 448.230 495.720 449.230 498.170 ;
        RECT 450.070 495.720 451.070 498.170 ;
        RECT 451.910 495.720 452.910 498.170 ;
        RECT 453.750 495.720 454.750 498.170 ;
        RECT 455.590 495.720 456.590 498.170 ;
        RECT 457.430 495.720 458.430 498.170 ;
        RECT 459.270 495.720 460.270 498.170 ;
        RECT 461.110 495.720 462.110 498.170 ;
        RECT 462.950 495.720 463.950 498.170 ;
        RECT 464.790 495.720 465.790 498.170 ;
        RECT 466.630 495.720 467.630 498.170 ;
        RECT 468.470 495.720 469.470 498.170 ;
        RECT 470.310 495.720 479.690 498.170 ;
        RECT 17.110 4.280 479.690 495.720 ;
        RECT 17.110 4.000 62.370 4.280 ;
        RECT 63.210 4.000 187.030 4.280 ;
        RECT 187.870 4.000 311.690 4.280 ;
        RECT 312.530 4.000 436.350 4.280 ;
        RECT 437.190 4.000 479.690 4.280 ;
      LAYER met3 ;
        RECT 4.400 483.800 496.000 484.665 ;
        RECT 4.000 453.920 496.000 483.800 ;
        RECT 4.400 452.520 496.000 453.920 ;
        RECT 4.000 422.640 496.000 452.520 ;
        RECT 4.400 421.240 496.000 422.640 ;
        RECT 4.000 391.360 496.000 421.240 ;
        RECT 4.400 389.960 496.000 391.360 ;
        RECT 4.000 360.080 496.000 389.960 ;
        RECT 4.400 358.680 496.000 360.080 ;
        RECT 4.000 328.800 496.000 358.680 ;
        RECT 4.400 327.400 496.000 328.800 ;
        RECT 4.000 297.520 496.000 327.400 ;
        RECT 4.400 296.120 496.000 297.520 ;
        RECT 4.000 266.240 496.000 296.120 ;
        RECT 4.400 264.840 496.000 266.240 ;
        RECT 4.000 249.920 496.000 264.840 ;
        RECT 4.000 248.520 495.600 249.920 ;
        RECT 4.000 234.960 496.000 248.520 ;
        RECT 4.400 233.560 496.000 234.960 ;
        RECT 4.000 203.680 496.000 233.560 ;
        RECT 4.400 202.280 496.000 203.680 ;
        RECT 4.000 172.400 496.000 202.280 ;
        RECT 4.400 171.000 496.000 172.400 ;
        RECT 4.000 141.120 496.000 171.000 ;
        RECT 4.400 139.720 496.000 141.120 ;
        RECT 4.000 109.840 496.000 139.720 ;
        RECT 4.400 108.440 496.000 109.840 ;
        RECT 4.000 78.560 496.000 108.440 ;
        RECT 4.400 77.160 496.000 78.560 ;
        RECT 4.000 47.280 496.000 77.160 ;
        RECT 4.400 45.880 496.000 47.280 ;
        RECT 4.000 16.000 496.000 45.880 ;
        RECT 4.400 15.135 496.000 16.000 ;
      LAYER met4 ;
        RECT 51.815 449.440 438.545 482.625 ;
        RECT 51.815 52.535 65.260 449.440 ;
        RECT 67.660 52.535 68.560 449.440 ;
        RECT 70.960 52.535 218.860 449.440 ;
        RECT 221.260 52.535 222.160 449.440 ;
        RECT 224.560 52.535 372.460 449.440 ;
        RECT 374.860 52.535 375.760 449.440 ;
        RECT 378.160 52.535 438.545 449.440 ;
  END
END highpass
END LIBRARY

